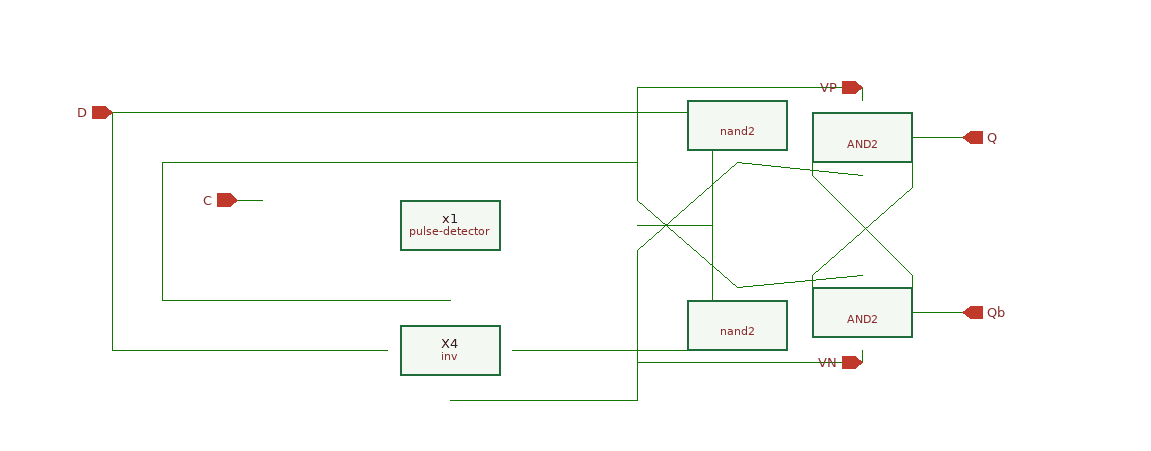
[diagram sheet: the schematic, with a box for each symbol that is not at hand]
v {xschem version=3.4.8RC file_version=1.3}
G {}
K {}
V {}
S {}
F {}
E {}
L 4 240 -70 240 -30 {}
L 4 160 40 160 60 {}
L 4 160 40 240 -30 {}
L 4 160 -60 160 -40 {}
L 4 240 40 240 70 {}
L 4 160 -40 240 40 {}
L 4 200 -110 200 -100 {}
L 4 200 100 200 110 {}
L 4 20 -110 20 -20 {}
L 4 20 -110 100 -110 {}
L 4 20 -20 100 50 {}
L 4 20 20 100 -50 {}
L 4 20 20 20 100 {}
L 4 80 -60 80 70 {}
L 4 20 0 80 -0 {}
L 4 20 110 100 110 {}
L 4 20 100 20 110 {}
L 4 -260 -90 80 -90 {}
L 4 240 70 280 70 {}
L 4 240 -70 280 -70 {}
L 4 -300 -20 -280 -20 {}
L 4 160 80 170 80 {}
L 4 -360 -50 20 -50 {}
L 4 -80 100 80 100 {}
L 4 -360 60 -130 60 {}
L 4 -360 -50 -360 60 {}
L 4 -130 140 20 140 {}
L 4 20 110 20 140 {}
L 4 -400 100 -180 100 {}
L 4 -400 -90 -400 100 {}
L 4 -400 -90 -260 -90 {}
L 4 160 60 170 60 {}
L 4 160 -60 170 -60 {}
L 4 230 70 240 70 {}
L 4 230 -70 240 -70 {}
L 4 160 -80 170 -80 {}
L 4 100 -110 200 -110 {}
L 4 100 110 200 110 {}
L 4 100 -50 200 -40 {}
L 4 100 50 200 40 {}
C {/home/madvlsi/madvlsi/mp1/xschem/nand2.sym} 100 -80 0 0 {}
C {/home/madvlsi/madvlsi/mp1/xschem/nand2.sym} 100 80 0 0 {}
C {opin.sym} 280 -70 0 0 {name=p1 lab=Q}
C {opin.sym} 280 70 0 0 {name=p2 lab=Qb
}
C {ipin.sym} -300 -20 0 0 {name=p3 lab=C}
C {pulse-detector.sym} -130 0 0 0 {name=x1}
C {/home/madvlsi/madvlsi/mp1/xschem/inv.sym} -130 100 0 0 {name=X4}
C {ipin.sym} -400 -90 0 0 {name=p4 lab=D}
C {AND2.sym} 200 -70 0 0 {}
C {AND2.sym} 200 70 0 0 {}
C {iopin.sym} 200 -110 0 0 {name=p5 lab=VP}
C {iopin.sym} 200 110 0 0 {name=p6 lab=VN}
